VERSION 5.7 ;
  NOWIREEXTENSIONATPIN ON ;
  DIVIDERCHAR "/" ;
  BUSBITCHARS "[]" ;
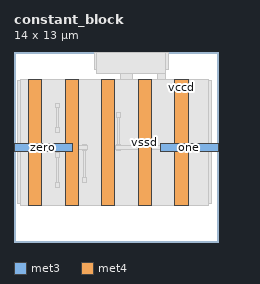
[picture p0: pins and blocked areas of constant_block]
MACRO constant_block
  CLASS BLOCK ;
  FOREIGN constant_block ;
  ORIGIN 0.000 0.000 ;
  SIZE 14.000 BY 13.000 ;
  PIN one
    DIRECTION OUTPUT TRISTATE ;
    USE SIGNAL ;
    ANTENNADIFFAREA 3.564000 ;
    PORT
      LAYER met3 ;
        RECT 10.000 6.160 14.000 6.760 ;
    END
  END one
  PIN vccd
    DIRECTION INOUT ;
    USE POWER ;
    ANTENNADIFFAREA 6.737500 ;
    PORT
      LAYER met4 ;
        RECT 11.010 2.480 11.910 11.120 ;
    END
    PORT
      LAYER met4 ;
        RECT 6.010 2.480 6.910 11.120 ;
    END
    PORT
      LAYER met4 ;
        RECT 1.010 2.480 1.910 11.120 ;
    END
  END vccd
  PIN vssd
    DIRECTION INOUT ;
    USE GROUND ;
    ANTENNADIFFAREA 4.364500 ;
    PORT
      LAYER met4 ;
        RECT 8.510 2.480 9.410 11.120 ;
    END
    PORT
      LAYER met4 ;
        RECT 3.510 2.480 4.410 11.120 ;
    END
  END vssd
  PIN zero
    DIRECTION OUTPUT TRISTATE ;
    USE SIGNAL ;
    ANTENNADIFFAREA 3.564000 ;
    PORT
      LAYER met3 ;
        RECT 0.000 6.160 4.000 6.760 ;
    END
  END zero
  OBS
      LAYER nwell ;
        RECT 0.270 2.635 13.530 11.070 ;
      LAYER li1 ;
        RECT 0.460 2.635 13.340 10.965 ;
      LAYER met1 ;
        RECT 0.460 2.480 13.340 11.120 ;
      LAYER met2 ;
        RECT 1.120 10.695 1.800 11.065 ;
        RECT 1.120 5.255 1.800 5.625 ;
        RECT 11.120 10.695 11.800 11.065 ;
        RECT 11.120 5.255 11.800 5.625 ;
        RECT 2.860 3.750 3.120 4.070 ;
        RECT 2.860 5.790 3.120 6.110 ;
        RECT 2.860 7.490 3.120 7.810 ;
        RECT 2.860 9.190 3.120 9.510 ;
        RECT 2.920 4.070 3.060 5.790 ;
        RECT 2.920 7.810 3.060 9.190 ;
        RECT 3.620 2.535 4.300 2.905 ;
        RECT 3.620 7.975 4.300 8.345 ;
        RECT 4.690 6.275 4.970 6.645 ;
        RECT 4.700 4.090 4.960 4.410 ;
        RECT 4.760 4.410 4.900 6.275 ;
        RECT 6.120 10.695 6.800 11.065 ;
        RECT 6.120 5.255 6.800 5.625 ;
        RECT 6.990 6.275 7.270 6.645 ;
        RECT 7.000 8.510 7.260 8.830 ;
        RECT 7.060 6.645 7.200 8.510 ;
        RECT 8.620 2.535 9.300 2.905 ;
        RECT 8.620 7.975 9.300 8.345 ;
      LAYER met3 ;
        RECT 1.070 10.715 1.850 11.045 ;
        RECT 1.070 5.275 1.850 5.605 ;
        RECT 11.070 10.715 11.850 11.045 ;
        RECT 11.070 5.275 11.850 5.605 ;
        RECT 3.570 2.555 4.350 2.885 ;
        RECT 3.570 7.995 4.350 8.325 ;
        RECT 4.000 6.310 4.995 6.610 ;
        RECT 4.665 6.295 4.995 6.310 ;
        RECT 4.665 6.610 4.995 6.625 ;
        RECT 5.490 11.790 7.395 13.000 ;
        RECT 6.070 10.715 6.850 11.045 ;
        RECT 6.070 5.275 6.850 5.605 ;
        RECT 6.965 6.295 7.295 6.310 ;
        RECT 6.965 6.310 10.000 6.610 ;
        RECT 6.965 6.610 7.295 6.625 ;
        RECT 8.325 11.790 10.575 13.000 ;
        RECT 8.570 2.555 9.350 2.885 ;
        RECT 8.570 7.995 9.350 8.325 ;
      LAYER met4 ;
        RECT 5.625 11.520 10.380 13.000 ;
        RECT 7.310 11.120 8.110 11.520 ;
        RECT 9.810 11.120 10.380 11.520 ;
  END
END constant_block
END LIBRARY
